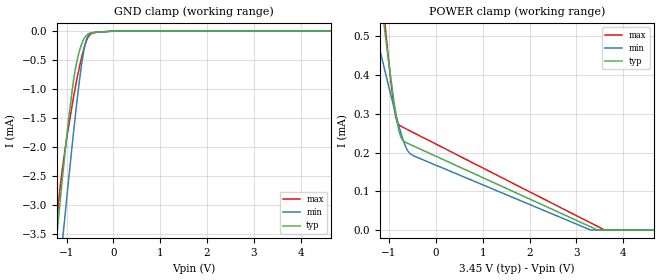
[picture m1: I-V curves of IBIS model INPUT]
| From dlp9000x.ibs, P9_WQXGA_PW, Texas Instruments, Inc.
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|   Model
[Model]   INPUT
Model_type   Input
Vinl = 0.7
Vinh = 1.7
|   typ   min   max
C_comp   0.532pF   0.482pF   0.599pF
[Voltage Range]   3.45   3.3   3.6
[Temperature Range]   25   125   -40
[Power Clamp Reference]   3.45   3.3   3.6
[GND Clamp Reference]   -0   -0   -0
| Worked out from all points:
|   GND clamp passes 1 mA (typ) near -0.88 V on its own axis
|   POWER clamp passes 1 mA (typ) near -1.57 V on its own axis
[GND Clamp]
|   Voltage   I(typ)   I(min)   I(max)
-3.45V    -23.97mA   -25.15mA   -25.67mA
-1.256V   -3.943mA   -5.035mA   -3.635mA
-1.142V   -2.98mA    -4.08mA    -2.727mA
-1.09V    -2.555mA   -3.652mA   -2.382mA
-1.028V   -2.06mA    -3.144mA   -2.022mA
-862.5mV  -912.3uA   -1.836mA   -1.193mA
-800.4mV  -606.8uA   -1.375mA   -918.5uA
-645.2mV  -161.3uA   -400.9uA   -346.4uA
-572.7mV  -70.94uA   -140.9uA   -161.6uA
-521mV    -42.12uA   -61.44uA   -81.77uA
-3.45mV   -186.6nA   -170.6nA   -209.3nA
6.89V     0A         0A         0A
[POWER Clamp]
|   Voltage   I(typ)   I(min)   I(max)
-3.45V    2.979mA    1.656mA    3.656mA
-1.38V    804.7uA    559.5uA    903.7uA
-1.276V   699.4uA    506.2uA    770.2uA
-1.09V    513.5uA    411.7uA    535.4uA
-862.5mV  305.7uA    301.1uA    294.7uA
-779.7mV  251.9uA    264uA      270.7uA
-707.3mV  231.7uA    234.9uA    265.5uA
-603.8mV  223.8uA    204.9uA    259.1uA
-469.2mV  216.3uA    191.3uA    250.8uA
3.298V    8.373uA    86.64nA    18.59uA
3.598V    0A         0A         98.41nA
6.89V     0A         0A         0A
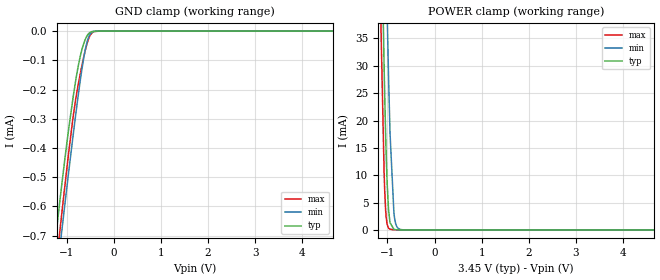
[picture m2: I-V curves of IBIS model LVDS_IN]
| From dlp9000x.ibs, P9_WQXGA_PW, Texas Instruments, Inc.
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|   Model
[Model]   LVDS_IN
Model_type   Input
Vinl = 0.7
Vinh = 1.7
|   typ   min   max
C_comp   0.650pF   0.629pF   0.687pF
[Voltage Range]   3.45   3.3   3.6
[Temperature Range]   25   125   -40
[Power Clamp Reference]   3.45   3.3   3.6
[GND Clamp Reference]   -0   -0   -0
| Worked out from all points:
|   GND clamp passes 1 mA (typ) near -1.43 V on its own axis
|   POWER clamp passes 1 mA (typ) near -0.92 V on its own axis
[GND Clamp]
|   Voltage   I(typ)   I(min)   I(max)
-3.45V    -4.153mA   -4.175mA   -4.739mA
-1.266V   -756uA     -915.2uA   -866.8uA
-1.142V   -579.4uA   -739.3uA   -682uA
-1.132V   -565uA     -724.8uA   -666.8uA
-1.049V   -452.9uA   -609.3uA   -546.5uA
-862.5mV  -226.5uA   -357.3uA   -293.7uA
-759mV    -124.3uA   -226.3uA   -187.4uA
-676.2mV  -63.96uA   -131.6uA   -117.9uA
-603.8mV  -28.35uA   -63.42uA   -65.27uA
-489.9mV  -3.437uA   -8.323uA   -11.88uA
-282.9mV  -4.641nA   -35.76nA   -10.96nA
6.89V     0A         0A         0A
[POWER Clamp]
|   Voltage   I(typ)   I(min)   I(max)
-3.45V    1.548A     1.585A     1.53A
-1.142V   64.18mA    107.5mA    39.91mA
-1.132V   58.78mA    101.8mA    34.84mA
-1.069V   29.34mA    69.25mA    10.15mA
-1.038V   17.53mA    54.18mA    3.636mA
-1.007V   8.802mA    40.28mA    1.05mA
-976.4mV  3.641mA    27.96mA    326.4uA
-945.3mV  1.327mA    17.73mA    136.8uA
-862.5mV  122.2uA    3.083mA    24.81uA
-810.7mV  43.24uA    803uA      6.391uA
-727.9mV  6.193uA    107.9uA    1.976uA
6.89V     0A         0A         0A
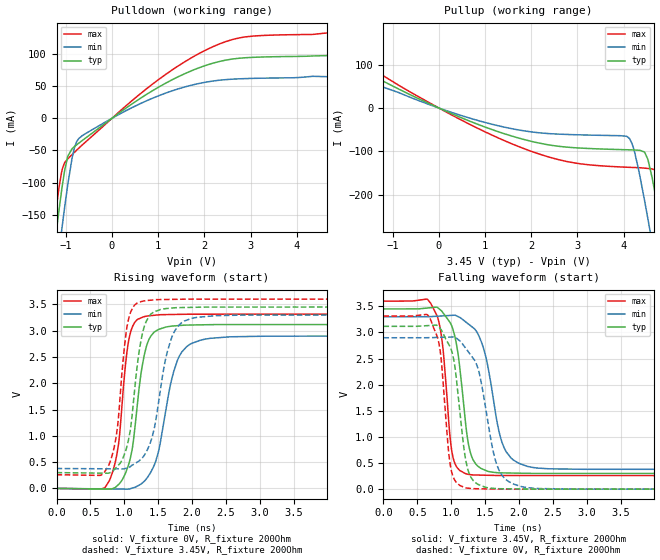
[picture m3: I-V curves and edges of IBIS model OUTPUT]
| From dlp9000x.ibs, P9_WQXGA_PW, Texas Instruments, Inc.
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|   Model
[Model]   OUTPUT
Model_type   Output
Polarity   Non-Inverting
Vmeas = 1.725
Vref = 0
Cref = 1pF
Rref = 100000
|   typ   min   max
C_comp   1.893pF   1.813pF   2.012pF
[Voltage Range]   3.45   3.3   3.6
[Temperature Range]   25   125   -40
[Pullup Reference]   3.45   3.3   3.6
[Pulldown Reference]   -0   -0   -0
[Power Clamp Reference]   3.45   3.3   3.6
[GND Clamp Reference]   -0   -0   -0
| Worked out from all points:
|   slope of the pulldown table from 0 to 0.517 V, typ, clamps not added: 19.6 ohm
|   slope of the pullup table from 0 to 0.517 V, typ, clamps not added: 21.7 ohm
|   falling waveform, V_fixture 3.45V, R_fixture 200Ohm: 20-80 % time 175ps typ, 262ps min, 133ps max; typ from 3.45 V to 0.301 V
|   rising waveform, V_fixture 0V, R_fixture 200Ohm: 20-80 % time 191ps typ, 276ps min, 153ps max; typ from 0 V to 3.12 V
|   rising waveform, V_fixture 3.45V, R_fixture 200Ohm: 20-80 % time 184ps typ, 254ps min, 152ps max; typ from 0.301 V to 3.45 V
|   falling waveform, V_fixture 0V, R_fixture 200Ohm: 20-80 % time 171ps typ, 254ps min, 129ps max; typ from 3.12 V to 0 V
[Pulldown]
|   Voltage   I(typ)   I(min)   I(max)
-3.45V    -1.628A    -1.69A     -1.592A
-1.266V   -212.3mA   -279.3mA   -173.5mA
-1.163V   -151.7mA   -217.1mA   -115.9mA
-1.069V   -102mA     -163.2mA   -77.52mA
-955.6mV  -58.81mA   -102.3mA   -62.87mA
-862.5mV  -47.16mA   -61.34mA   -56.29mA
-810.7mV  -43.88mA   -45.35mA   -52.7mA
-717.6mV  -38.57mA   -31.39mA   -46.34mA
876.3mV   42.78mA    31.13mA    53.02mA
2.325V    88.24mA    59.14mA    115.5mA
3.05V     94.66mA    61.99mA    127.6mA
6.89V     106.9mA    71.84mA    141.9mA
[Pullup]
|   Voltage   I(typ)   I(min)   I(max)
-3.45V    156.2mA    129.6mA    186.4mA
-1.349V   67.79mA    52.58mA    83.75mA
1.632V    -66.5mA    -48.88mA   -84.99mA
2.76V     -90.32mA   -61.07mA   -123.4mA
4.064V    -96.43mA   -65.59mA   -136.8mA
4.219V    -96.95mA   -95.68mA   -137.5mA
4.447V    -101.7mA   -211.4mA   -138.8mA
4.53V     -121.7mA   -259.9mA   -139.8mA
4.613V    -159.8mA   -309.8mA   -140.9mA
4.809V    -272.6mA   -431.5mA   -160mA
5.037V    -414mA     -575.6mA   -282.8mA
6.89V     -1.622A    -1.783A    -1.487A
[Ramp]
R_load = 200
|   typ   min   max
dV/dt_r   1.87039/1.89658e-10   1.73921/2.72027e-10   1.9883/1.52446e-10
dV/dt_f   1.88959/1.74521e-10   1.75268/2.61584e-10   2.00394/1.32949e-10
[Falling Waveform]
V_fixture = 3.45V
V_fixture_min = 3.3V
V_fixture_max = 3.6V
R_fixture = 200Ohm
C_fixture = 0F
|   Time   V(typ)   V(min)   V(max)
0s        3.45V      3.3V       3.6V
783.2ps   3.485V     3.31V      3.341V
879.5ps   3.375V     3.317V     2.688V
1.014ns   3.107V     3.328V     692.1mV
1.214ns   1.237V     3.202V     295.8mV
1.308ns   605.2mV    3.107V     273.4mV
1.479ns   375.4mV    2.688V     267.8mV
1.782ns   310.8mV    788.8mV    260.7mV
2.129ns   303.2mV    434.5mV    260.6mV
10ns      300.7mV    378.8mV    260.1mV
[Rising Waveform]
V_fixture = 0V
V_fixture_min = 0V
V_fixture_max = 0V
R_fixture = 200Ohm
C_fixture = 0F
|   Time   V(typ)   V(min)   V(max)
0s        16.37uV    34.56uV    844.1nV
775.8ps   -12.61mV   -10.6mV    139.2mV
911.1ps   70.04mV    -12.45mV   810mV
1.014ns   279.8mV    -13.85mV   2.304V
1.086ns   555.3mV    -6.733mV   2.936V
1.28ns    2.438V     119.4mV    3.261V
1.5ns     3.019V     679.1mV    3.299V
1.782ns   3.094V     2.431V     3.308V
2.129ns   3.11V      2.82V      3.312V
10ns      3.117V     2.899V     3.314V
[Rising Waveform]
V_fixture = 3.45V
V_fixture_min = 3.3V
V_fixture_max = 3.6V
R_fixture = 200Ohm
C_fixture = 0F
|   Time   V(typ)   V(min)   V(max)
0s        300.7mV    378.8mV    260.1mV
768.4ps   290.6mV    372.6mV    437.7mV
897.4ps   420.4mV    371.6mV    1.147V
987ps     600.1mV    370.8mV    2.51V
1.058ns   897.6mV    395.3mV    3.193V
1.254ns   2.868V     565.8mV    3.554V
1.409ns   3.331V     968.3mV    3.581V
1.68ns    3.427V     2.798V     3.593V
1.994ns   3.442V     3.233V     3.599V
10ns      3.45V      3.3V       3.6V
[Falling Waveform]
|Gnd
V_fixture = 0V
V_fixture_min = 0V
V_fixture_max = 0V
R_fixture = 200Ohm
C_fixture = 0F
|   Time   V(typ)   V(min)   V(max)
0s        3.117V     2.899V     3.314V
690.3ps   3.134V     2.901V     3.261V
837.2ps   3.076V     2.906V     2.649V
960.6ps   2.78V      2.911V     732.2mV
1.012ns   2.622V     2.912V     301.3mV
1.199ns   675.5mV    2.724V     30.34mV
1.409ns   84.36mV    2.248V     7.802mV
1.68ns    10.58mV    443.4mV    1.335mV
2.03ns    3.397mV    51.35mV    361.6uV
10ns      16.37uV    34.91uV    844.1nV
